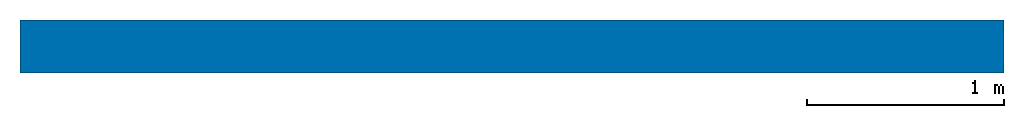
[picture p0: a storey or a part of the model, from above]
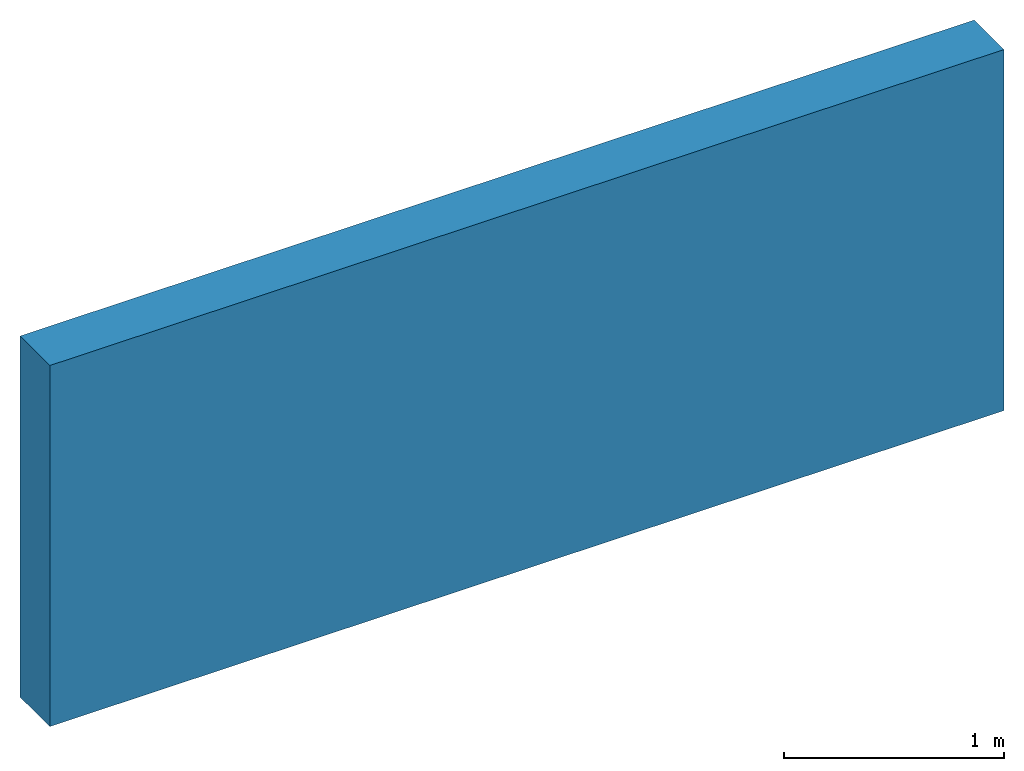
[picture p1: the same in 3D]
Properties of the parts of a building model (IFC4)

# File
Description: ViewDefinition [DesignTransferView_V1]
Time: 2016-02-04T08:47:55
Author: Jon
Organization: Unknown
Written by: GeomGymIFC by Geometry Gym Pty Ltd
Made in: Unknown Application
Comment: name
Comment: time_stamp
Comment: author
Comment: organization
Comment: preprocessor_version
Comment: originating_system
Comment: authorization
Comment: general entities required for all IFC data sets, defining the context for the exchange
Comment: defines the default building (as required as the minimum spatial element)

# IfcWall: Double Brick - 270
In: IfcBuilding
Type - Material: Masonry - Brick - Brown 110 mm, layer 50 mm, Masonry 110 mm
